VERSION 5.8 ;
BUSBITCHARS "[]" ;
DIVIDERCHAR "/" ;
UNITS
    DATABASE MICRONS 1000 ;
END UNITS

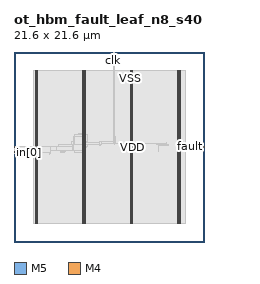
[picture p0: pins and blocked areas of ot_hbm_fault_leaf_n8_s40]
MACRO ot_hbm_fault_leaf_n8_s40
  FOREIGN ot_hbm_fault_leaf_n8_s40 0 0 ;
  CLASS BLOCK ;
  SIZE 21.6 BY 21.6 ;
  PIN clk
    DIRECTION INPUT ;
    USE SIGNAL ;
    PORT
      LAYER M5 ;
        RECT  11.28 21.516 11.304 21.6 ;
    END
  END clk
  PIN fault
    DIRECTION OUTPUT ;
    USE SIGNAL ;
    PORT
      LAYER M4 ;
        RECT  21.516 10.8 21.6 10.824 ;
    END
  END fault
  PIN in[0]
    DIRECTION INPUT ;
    USE SIGNAL ;
    PORT
      LAYER M4 ;
        RECT  0 10.128 0.084 10.152 ;
    END
  END in[0]
  PIN in[1]
    DIRECTION INPUT ;
    USE SIGNAL ;
    PORT
      LAYER M4 ;
        RECT  0 10.224 0.084 10.248 ;
    END
  END in[1]
  PIN in[2]
    DIRECTION INPUT ;
    USE SIGNAL ;
    PORT
      LAYER M4 ;
        RECT  0 10.32 0.084 10.344 ;
    END
  END in[2]
  PIN in[3]
    DIRECTION INPUT ;
    USE SIGNAL ;
    PORT
      LAYER M4 ;
        RECT  0 10.416 0.084 10.44 ;
    END
  END in[3]
  PIN in[4]
    DIRECTION INPUT ;
    USE SIGNAL ;
    PORT
      LAYER M4 ;
        RECT  0 10.512 0.084 10.536 ;
    END
  END in[4]
  PIN in[5]
    DIRECTION INPUT ;
    USE SIGNAL ;
    PORT
      LAYER M4 ;
        RECT  0 10.608 0.084 10.632 ;
    END
  END in[5]
  PIN in[6]
    DIRECTION INPUT ;
    USE SIGNAL ;
    PORT
      LAYER M4 ;
        RECT  0 10.704 0.084 10.728 ;
    END
  END in[6]
  PIN in[7]
    DIRECTION INPUT ;
    USE SIGNAL ;
    PORT
      LAYER M4 ;
        RECT  0 10.8 0.084 10.824 ;
    END
  END in[7]
  PIN rst_n
    DIRECTION INPUT ;
    USE SIGNAL ;
    PORT
      LAYER M5 ;
        RECT  11.376 21.516 11.4 21.6 ;
    END
  END rst_n
  PIN VDD
    DIRECTION INOUT ;
    USE POWER ;
    PORT
      LAYER M5 ;
        RECT  18.792 2.151 18.912 19.449 ;
        RECT  13.392 2.151 13.512 19.449 ;
        RECT  7.992 2.151 8.112 19.449 ;
        RECT  2.592 2.151 2.712 19.449 ;
    END
  END VDD
  PIN VSS
    DIRECTION INOUT ;
    USE GROUND ;
    PORT
      LAYER M5 ;
        RECT  18.6 2.137 18.72 19.463 ;
        RECT  13.2 2.137 13.32 19.463 ;
        RECT  7.8 2.137 7.92 19.463 ;
        RECT  2.4 2.137 2.52 19.463 ;
    END
  END VSS
  OBS
    LAYER RVTN ;
     RECT  2.16 2.16 19.44 2.295 ;
     RECT  2.16 2.565 19.44 2.835 ;
     RECT  2.16 3.105 19.44 3.375 ;
     RECT  2.16 3.645 19.44 3.915 ;
     RECT  2.16 4.185 19.44 4.455 ;
     RECT  2.16 4.725 19.44 4.995 ;
     RECT  2.16 5.265 19.44 5.535 ;
     RECT  2.16 5.805 19.44 6.075 ;
     RECT  2.16 6.345 19.44 6.615 ;
     RECT  2.16 6.885 19.44 7.155 ;
     RECT  2.16 7.425 19.44 7.695 ;
     RECT  2.16 7.965 19.44 8.235 ;
     RECT  2.16 8.505 19.44 8.775 ;
     RECT  2.16 9.045 19.44 9.315 ;
     RECT  2.16 9.585 19.44 9.855 ;
     RECT  2.16 10.125 19.44 10.395 ;
     RECT  2.16 10.665 19.44 10.935 ;
     RECT  2.16 11.205 19.44 11.475 ;
     RECT  2.16 11.745 19.44 12.015 ;
     RECT  2.16 12.285 19.44 12.555 ;
     RECT  2.16 12.825 19.44 13.095 ;
     RECT  2.16 13.365 19.44 13.635 ;
     RECT  2.16 13.905 19.44 14.175 ;
     RECT  2.16 14.445 19.44 14.715 ;
     RECT  2.16 14.985 19.44 15.255 ;
     RECT  2.16 15.525 19.44 15.795 ;
     RECT  2.16 16.065 19.44 16.335 ;
     RECT  2.16 16.605 19.44 16.875 ;
     RECT  2.16 17.145 19.44 17.415 ;
     RECT  2.16 17.685 19.44 17.955 ;
     RECT  2.16 18.225 19.44 18.495 ;
     RECT  2.16 18.765 19.44 19.035 ;
     RECT  2.16 19.305 19.44 19.44 ;
    LAYER RVTP ;
     RECT  2.16 2.295 19.44 2.565 ;
     RECT  2.16 2.835 19.44 3.105 ;
     RECT  2.16 3.375 19.44 3.645 ;
     RECT  2.16 3.915 19.44 4.185 ;
     RECT  2.16 4.455 19.44 4.725 ;
     RECT  2.16 4.995 19.44 5.265 ;
     RECT  2.16 5.535 19.44 5.805 ;
     RECT  2.16 6.075 19.44 6.345 ;
     RECT  2.16 6.615 19.44 6.885 ;
     RECT  2.16 7.155 19.44 7.425 ;
     RECT  2.16 7.695 19.44 7.965 ;
     RECT  2.16 8.235 19.44 8.505 ;
     RECT  2.16 8.775 19.44 9.045 ;
     RECT  2.16 9.315 19.44 9.585 ;
     RECT  2.16 9.855 19.44 10.125 ;
     RECT  2.16 10.395 19.44 10.665 ;
     RECT  2.16 10.935 19.44 11.205 ;
     RECT  2.16 11.475 19.44 11.745 ;
     RECT  2.16 12.015 19.44 12.285 ;
     RECT  2.16 12.555 19.44 12.825 ;
     RECT  2.16 13.095 19.44 13.365 ;
     RECT  2.16 13.635 19.44 13.905 ;
     RECT  2.16 14.175 19.44 14.445 ;
     RECT  2.16 14.715 19.44 14.985 ;
     RECT  2.16 15.255 19.44 15.525 ;
     RECT  2.16 15.795 19.44 16.065 ;
     RECT  2.16 16.335 19.44 16.605 ;
     RECT  2.16 16.875 19.44 17.145 ;
     RECT  2.16 17.415 19.44 17.685 ;
     RECT  2.16 17.955 19.44 18.225 ;
     RECT  2.16 18.495 19.44 18.765 ;
     RECT  2.16 19.035 19.44 19.305 ;
    LAYER M1 ;
     RECT  2.16 2.151 19.44 19.449 ;
    LAYER M2 ;
     RECT  2.16 2.151 19.44 19.449 ;
     RECT  19.44 10.836 21.515 10.854 ;
    LAYER M3 ;
     RECT  2.415 2.143 2.505 2.413 ;
     RECT  7.815 2.143 7.905 2.413 ;
     RECT  13.215 2.143 13.305 2.413 ;
     RECT  18.615 2.143 18.705 2.413 ;
     RECT  4.068 9.931 4.086 10.093 ;
     RECT  2.415 2.413 2.697 10.123 ;
     RECT  2.412 10.123 2.697 10.129 ;
     RECT  5.688 10.129 5.706 10.165 ;
     RECT  7.815 2.413 8.097 10.165 ;
     RECT  0.108 10.027 0.126 10.253 ;
     RECT  5.256 10.165 5.706 10.291 ;
     RECT  2.412 10.129 3.222 10.315 ;
     RECT  5.256 10.291 5.814 10.399 ;
     RECT  6.876 10.165 8.097 10.399 ;
     RECT  5.256 10.399 8.097 10.435 ;
     RECT  4.068 10.093 4.194 10.459 ;
     RECT  5.256 10.435 8.154 10.459 ;
     RECT  4.068 10.459 8.154 10.741 ;
     RECT  2.304 10.315 3.222 10.829 ;
     RECT  2.304 10.829 2.862 10.859 ;
     RECT  21.492 10.795 21.51 10.859 ;
     RECT  2.415 10.859 2.862 10.895 ;
     RECT  4.068 10.741 8.19 10.895 ;
     RECT  5.004 10.895 8.19 10.903 ;
     RECT  9.756 10.975 9.774 11.011 ;
     RECT  16.38 10.327 16.398 11.011 ;
     RECT  5.004 10.903 8.334 11.039 ;
     RECT  5.724 11.039 8.334 11.129 ;
     RECT  16.38 11.011 17.514 11.129 ;
     RECT  16.38 11.129 17.298 11.137 ;
     RECT  11.412 11.101 11.43 11.173 ;
     RECT  9.756 11.011 9.882 11.179 ;
     RECT  11.412 11.173 11.574 11.201 ;
     RECT  14.832 11.011 14.85 11.201 ;
     RECT  16.236 11.137 17.298 11.201 ;
     RECT  16.236 11.201 16.254 11.213 ;
     RECT  17.28 11.201 17.298 11.273 ;
     RECT  9.756 11.179 9.99 11.309 ;
     RECT  9.756 11.309 9.774 11.405 ;
     RECT  6.516 11.129 8.334 11.435 ;
     RECT  11.556 11.201 11.574 11.939 ;
     RECT  11.376 11.947 11.394 11.984 ;
     RECT  6.84 11.435 8.334 12.209 ;
     RECT  6.84 12.209 8.097 12.245 ;
     RECT  7.308 12.245 8.097 12.281 ;
     RECT  2.415 10.895 2.697 19.187 ;
     RECT  7.815 12.281 8.097 19.187 ;
     RECT  13.215 2.413 13.497 19.187 ;
     RECT  18.615 2.413 18.897 19.187 ;
     RECT  2.415 19.187 2.505 19.457 ;
     RECT  7.815 19.187 7.905 19.457 ;
     RECT  13.215 19.187 13.305 19.457 ;
     RECT  18.615 19.187 18.705 19.457 ;
    LAYER M4 ;
     RECT  0.06 10.128 0.097 10.824 ;
     RECT  0.097 10.032 2.408 10.824 ;
     RECT  2.408 2.148 2.512 19.452 ;
     RECT  2.512 2.418 2.704 19.182 ;
     RECT  2.704 10.176 4.097 10.824 ;
     RECT  4.097 10.416 4.816 10.824 ;
     RECT  4.816 10.416 6.685 10.872 ;
     RECT  6.685 10.416 6.815 11.064 ;
     RECT  6.815 10.416 7.808 11.976 ;
     RECT  7.808 2.148 7.912 19.452 ;
     RECT  7.912 2.418 8.104 19.182 ;
     RECT  8.104 11.136 9.745 11.304 ;
     RECT  9.745 11.136 9.893 11.4 ;
     RECT  9.893 11.184 11.365 11.4 ;
     RECT  11.365 11.184 11.449 11.976 ;
     RECT  11.449 11.184 13.208 11.208 ;
     RECT  13.208 2.148 13.312 19.452 ;
     RECT  13.312 2.418 13.504 19.182 ;
     RECT  13.504 11.184 16.265 11.208 ;
     RECT  18.608 2.148 18.712 19.452 ;
     RECT  18.712 2.418 18.904 19.182 ;
     RECT  21.481 10.8 21.564 10.824 ;
    LAYER M5 ;
     RECT  2.4 2.137 2.52 2.151 ;
     RECT  7.8 2.137 7.92 2.151 ;
     RECT  13.2 2.137 13.32 2.151 ;
     RECT  18.6 2.137 18.72 2.151 ;
     RECT  7.8 2.151 8.112 11.029 ;
     RECT  11.28 11.365 11.304 11.941 ;
     RECT  6.864 11.029 8.112 11.987 ;
     RECT  2.4 2.151 2.712 19.449 ;
     RECT  7.8 11.987 8.112 19.449 ;
     RECT  13.2 2.151 13.512 19.449 ;
     RECT  18.6 2.151 18.912 19.449 ;
     RECT  2.4 19.449 2.52 19.463 ;
     RECT  7.8 19.449 7.92 19.463 ;
     RECT  13.2 19.449 13.32 19.463 ;
     RECT  18.6 19.449 18.72 19.463 ;
     RECT  11.28 11.941 11.4 21.584 ;
  END
END ot_hbm_fault_leaf_n8_s40
END LIBRARY
